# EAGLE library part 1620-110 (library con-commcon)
COMPACT PCI TYPE A - 110 PINS 2mm HARD METRIC SOCKETS

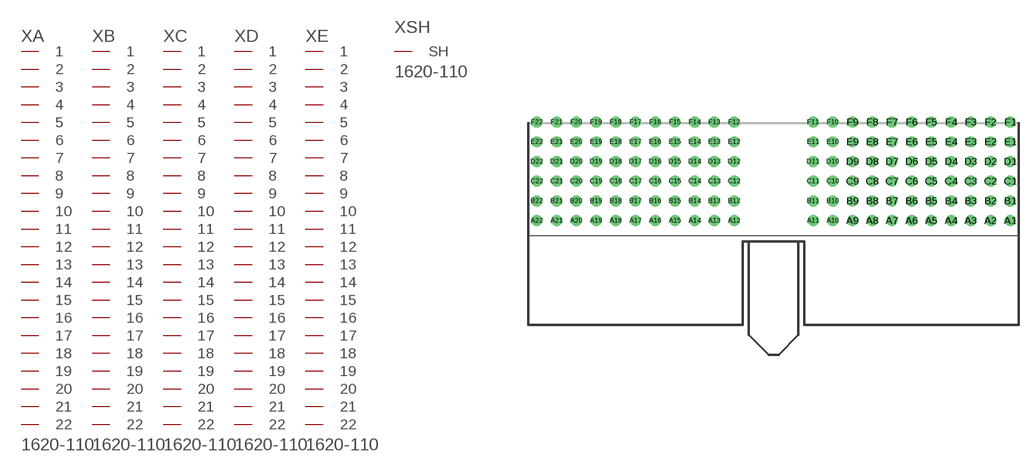
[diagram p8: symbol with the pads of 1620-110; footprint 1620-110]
Designator prefix X; gates A=PIN22 B=PIN22 C=PIN22 D=PIN22 E=PIN22 SH=SHIELD

## 1620-110  [1620-110]
A1  A:1  pas
A2  A:2  pas
A3  A:3  pas
A4  A:4  pas
A5  A:5  pas
A6  A:6  pas
A7  A:7  pas
A8  A:8  pas
A9  A:9  pas
A10  A:10  pas
A11  A:11  pas
A12  A:12  pas
A13  A:13  pas
A14  A:14  pas
A15  A:15  pas
A16  A:16  pas
A17  A:17  pas
A18  A:18  pas
A19  A:19  pas
A20  A:20  pas
A21  A:21  pas
A22  A:22  pas
B1  B:1  pas
B2  B:2  pas
B3  B:3  pas
B4  B:4  pas
B5  B:5  pas
B6  B:6  pas
B7  B:7  pas
B8  B:8  pas
B9  B:9  pas
B10  B:10  pas
B11  B:11  pas
B12  B:12  pas
B13  B:13  pas
B14  B:14  pas
B15  B:15  pas
B16  B:16  pas
B17  B:17  pas
B18  B:18  pas
B19  B:19  pas
B20  B:20  pas
B21  B:21  pas
B22  B:22  pas
C1  C:1  pas
C2  C:2  pas
C3  C:3  pas
C4  C:4  pas
C5  C:5  pas
C6  C:6  pas
C7  C:7  pas
C8  C:8  pas
C9  C:9  pas
C10  C:10  pas
C11  C:11  pas
C12  C:12  pas
C13  C:13  pas
C14  C:14  pas
C15  C:15  pas
C16  C:16  pas
C17  C:17  pas
C18  C:18  pas
C19  C:19  pas
C20  C:20  pas
C21  C:21  pas
C22  C:22  pas
D1  D:1  pas
D2  D:2  pas
D3  D:3  pas
D4  D:4  pas
D5  D:5  pas
D6  D:6  pas
D7  D:7  pas
D8  D:8  pas
D9  D:9  pas
D10  D:10  pas
D11  D:11  pas
D12  D:12  pas
D13  D:13  pas
D14  D:14  pas
D15  D:15  pas
D16  D:16  pas
D17  D:17  pas
D18  D:18  pas
D19  D:19  pas
D20  D:20  pas
D21  D:21  pas
D22  D:22  pas
E1  E:1  pas
E2  E:2  pas
E3  E:3  pas
E4  E:4  pas
E5  E:5  pas
E6  E:6  pas
E7  E:7  pas
E8  E:8  pas
E9  E:9  pas
E10  E:10  pas
E11  E:11  pas
E12  E:12  pas
E13  E:13  pas
E14  E:14  pas
E15  E:15  pas
E16  E:16  pas
E17  E:17  pas
E18  E:18  pas
E19  E:19  pas
E20  E:20  pas
E21  E:21  pas
E22  E:22  pas
F1  SH:SH  pas

## Footprint 1620-110 (pad centres in mm)
COMPACT PCI TYPE A - 110 PINS 2mm HARD METRIC SOCKETS
drill 0.6 round: A1 24,0; A2 22,0; A3 20,0; A4 18,0; A5 16,0; A6 14,0; A7 12,0; A8 10,0; A9 8,0; A10 6,0; A11 4,0; A12 -4,0; A13 -6,0; A14 -8,0; A15 -10,0; A16 -12,0; A17 -14,0; A18 -16,0; A19 -18,0; A20 -20,0; A21 -22,0; A22 -24,0; B1 24,2; B2 22,2; B3 20,2; B4 18,2; B5 16,2; B6 14,2; B7 12,2; B8 10,2; B9 8,2; B10 6,2; B11 4,2; B12 -4,2; B13 -6,2; B14 -8,2; B15 -10,2; B16 -12,2; B17 -14,2; B18 -16,2; B19 -18,2; B20 -20,2; B21 -22,2; B22 -24,2; C1 24,4; C2 22,4; C3 20,4; C4 18,4; C5 16,4; C6 14,4; C7 12,4; C8 10,4; C9 8,4; C10 6,4; C11 4,4; C12 -4,4; C13 -6,4; C14 -8,4; C15 -10,4; C16 -12,4; C17 -14,4; C18 -16,4; C19 -18,4; C20 -20,4; C21 -22,4; C22 -24,4; D1 24,6; D2 22,6; D3 20,6; D4 18,6; D5 16,6; D6 14,6; D7 12,6; D8 10,6; D9 8,6; D10 6,6; D11 4,6; D12 -4,6; D13 -6,6; D14 -8,6; D15 -10,6; D16 -12,6; D17 -14,6; D18 -16,6; D19 -18,6; D20 -20,6; D21 -22,6; D22 -24,6; E1 24,8; E2 22,8; E3 20,8; E4 18,8; E5 16,8; E6 14,8; E7 12,8; E8 10,8; E9 8,8; E10 6,8; E11 4,8; E12 -4,8; E13 -6,8; E14 -8,8; E15 -10,8; E16 -12,8; E17 -14,8; E18 -16,8; E19 -18,8; E20 -20,8; E21 -22,8; E22 -24,8; F1 24,10; F2 22,10; F3 20,10; F4 18,10; F5 16,10; F6 14,10; F7 12,10; F8 10,10; F9 8,10; F10 6,10; F11 4,10; F12 -4,10; F13 -6,10; F14 -8,10; F15 -10,10; F16 -12,10; F17 -14,10; F18 -16,10; F19 -18,10; F20 -20,10; F21 -22,10; F22 -24,10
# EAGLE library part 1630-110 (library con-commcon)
COMPACT PCI TYPE B - 110 PINS 2mm HARD METRIC SOCKETS

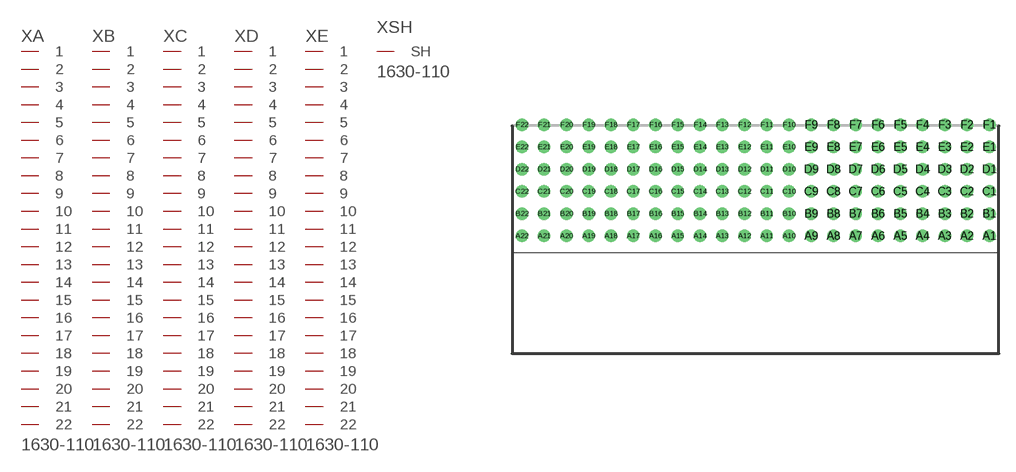
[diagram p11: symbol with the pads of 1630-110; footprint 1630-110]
Designator prefix X; gates A=PIN22 B=PIN22 C=PIN22 D=PIN22 E=PIN22 SH=SHIELD

## 1630-110  [1630-110]
A1  A:1  pas
A2  A:2  pas
A3  A:3  pas
A4  A:4  pas
A5  A:5  pas
A6  A:6  pas
A7  A:7  pas
A8  A:8  pas
A9  A:9  pas
A10  A:10  pas
A11  A:11  pas
A12  A:12  pas
A13  A:13  pas
A14  A:14  pas
A15  A:15  pas
A16  A:16  pas
A17  A:17  pas
A18  A:18  pas
A19  A:19  pas
A20  A:20  pas
A21  A:21  pas
A22  A:22  pas
B1  B:1  pas
B2  B:2  pas
B3  B:3  pas
B4  B:4  pas
B5  B:5  pas
B6  B:6  pas
B7  B:7  pas
B8  B:8  pas
B9  B:9  pas
B10  B:10  pas
B11  B:11  pas
B12  B:12  pas
B13  B:13  pas
B14  B:14  pas
B15  B:15  pas
B16  B:16  pas
B17  B:17  pas
B18  B:18  pas
B19  B:19  pas
B20  B:20  pas
B21  B:21  pas
B22  B:22  pas
C1  C:1  pas
C2  C:2  pas
C3  C:3  pas
C4  C:4  pas
C5  C:5  pas
C6  C:6  pas
C7  C:7  pas
C8  C:8  pas
C9  C:9  pas
C10  C:10  pas
C11  C:11  pas
C12  C:12  pas
C13  C:13  pas
C14  C:14  pas
C15  C:15  pas
C16  C:16  pas
C17  C:17  pas
C18  C:18  pas
C19  C:19  pas
C20  C:20  pas
C21  C:21  pas
C22  C:22  pas
D1  D:1  pas
D2  D:2  pas
D3  D:3  pas
D4  D:4  pas
D5  D:5  pas
D6  D:6  pas
D7  D:7  pas
D8  D:8  pas
D9  D:9  pas
D10  D:10  pas
D11  D:11  pas
D12  D:12  pas
D13  D:13  pas
D14  D:14  pas
D15  D:15  pas
D16  D:16  pas
D17  D:17  pas
D18  D:18  pas
D19  D:19  pas
D20  D:20  pas
D21  D:21  pas
D22  D:22  pas
E1  E:1  pas
E2  E:2  pas
E3  E:3  pas
E4  E:4  pas
E5  E:5  pas
E6  E:6  pas
E7  E:7  pas
E8  E:8  pas
E9  E:9  pas
E10  E:10  pas
E11  E:11  pas
E12  E:12  pas
E13  E:13  pas
E14  E:14  pas
E15  E:15  pas
E16  E:16  pas
E17  E:17  pas
E18  E:18  pas
E19  E:19  pas
E20  E:20  pas
E21  E:21  pas
E22  E:22  pas
F1  SH:SH  pas

## Footprint 1630-110 (pad centres in mm)
COMPACT PCI TYPE B - 110 PINS 2mm HARD METRIC SOCKETS
drill 0.6 round: A1 21,0; A2 19,0; A3 17,0; A4 15,0; A5 13,0; A6 11,0; A7 9,0; A8 7,0; A9 5,0; A10 3,0; A11 1,0; A12 -1,0; A13 -3,0; A14 -5,0; A15 -7,0; A16 -9,0; A17 -11,0; A18 -13,0; A19 -15,0; A20 -17,0; A21 -19,0; A22 -21,0; B1 21,2; B2 19,2; B3 17,2; B4 15,2; B5 13,2; B6 11,2; B7 9,2; B8 7,2; B9 5,2; B10 3,2; B11 1,2; B12 -1,2; B13 -3,2; B14 -5,2; B15 -7,2; B16 -9,2; B17 -11,2; B18 -13,2; B19 -15,2; B20 -17,2; B21 -19,2; B22 -21,2; C1 21,4; C2 19,4; C3 17,4; C4 15,4; C5 13,4; C6 11,4; C7 9,4; C8 7,4; C9 5,4; C10 3,4; C11 1,4; C12 -1,4; C13 -3,4; C14 -5,4; C15 -7,4; C16 -9,4; C17 -11,4; C18 -13,4; C19 -15,4; C20 -17,4; C21 -19,4; C22 -21,4; D1 21,6; D2 19,6; D3 17,6; D4 15,6; D5 13,6; D6 11,6; D7 9,6; D8 7,6; D9 5,6; D10 3,6; D11 1,6; D12 -1,6; D13 -3,6; D14 -5,6; D15 -7,6; D16 -9,6; D17 -11,6; D18 -13,6; D19 -15,6; D20 -17,6; D21 -19,6; D22 -21,6; E1 21,8; E2 19,8; E3 17,8; E4 15,8; E5 13,8; E6 11,8; E7 9,8; E8 7,8; E9 5,8; E10 3,8; E11 1,8; E12 -1,8; E13 -3,8; E14 -5,8; E15 -7,8; E16 -9,8; E17 -11,8; E18 -13,8; E19 -15,8; E20 -17,8; E21 -19,8; E22 -21,8; F1 21,10; F2 19,10; F3 17,10; F4 15,10; F5 13,10; F6 11,10; F7 9,10; F8 7,10; F9 5,10; F10 3,10; F11 1,10; F12 -1,10; F13 -3,10; F14 -5,10; F15 -7,10; F16 -9,10; F17 -11,10; F18 -13,10; F19 -15,10; F20 -17,10; F21 -19,10; F22 -21,10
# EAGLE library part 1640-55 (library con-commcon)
COMPACT PCI TYPE C - 55 PINS 2mm HARD METRIC SOCKETS

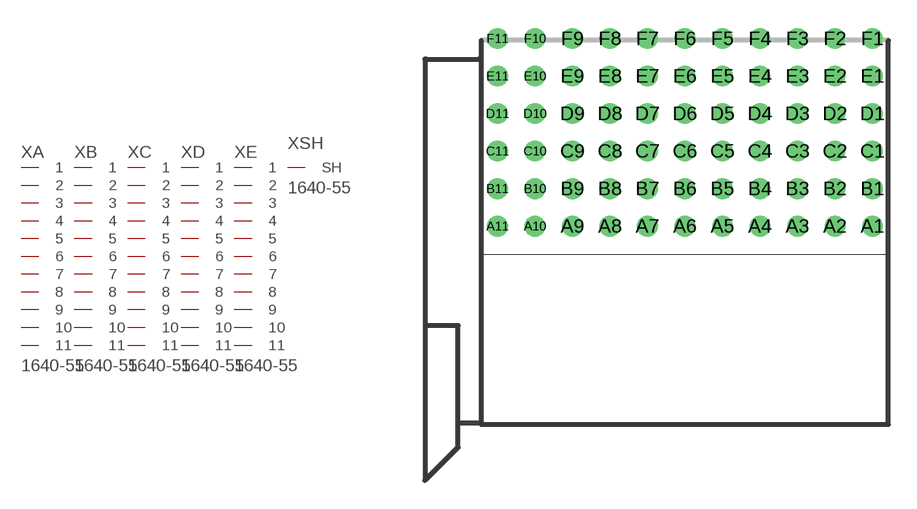
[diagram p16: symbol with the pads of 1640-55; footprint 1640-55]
Designator prefix X; gates A=PIN11 B=PIN11 C=PIN11 D=PIN11 E=PIN11 SH=SHIELD

## 1640-55  [1640-55]
A1  A:1  pas
A2  A:2  pas
A3  A:3  pas
A4  A:4  pas
A5  A:5  pas
A6  A:6  pas
A7  A:7  pas
A8  A:8  pas
A9  A:9  pas
A10  A:10  pas
A11  A:11  pas
B1  B:1  pas
B2  B:2  pas
B3  B:3  pas
B4  B:4  pas
B5  B:5  pas
B6  B:6  pas
B7  B:7  pas
B8  B:8  pas
B9  B:9  pas
B10  B:10  pas
B11  B:11  pas
C1  C:1  pas
C2  C:2  pas
C3  C:3  pas
C4  C:4  pas
C5  C:5  pas
C6  C:6  pas
C7  C:7  pas
C8  C:8  pas
C9  C:9  pas
C10  C:10  pas
C11  C:11  pas
D1  D:1  pas
D2  D:2  pas
D3  D:3  pas
D4  D:4  pas
D5  D:5  pas
D6  D:6  pas
D7  D:7  pas
D8  D:8  pas
D9  D:9  pas
D10  D:10  pas
D11  D:11  pas
E1  E:1  pas
E2  E:2  pas
E3  E:3  pas
E4  E:4  pas
E5  E:5  pas
E6  E:6  pas
E7  E:7  pas
E8  E:8  pas
E9  E:9  pas
E10  E:10  pas
E11  E:11  pas
F1  SH:SH  pas

## Footprint 1640-55 (pad centres in mm)
COMPACT PCI TYPE C - 55 PINS 2mm HARD METRIC SOCKETS
drill 0.6 round: A1 10,0; A2 8,0; A3 6,0; A4 4,0; A5 2,0; A6 0,0; A7 -2,0; A8 -4,0; A9 -6,0; A10 -8,0; A11 -10,0; B1 10,2; B2 8,2; B3 6,2; B4 4,2; B5 2,2; B6 0,2; B7 -2,2; B8 -4,2; B9 -6,2; B10 -8,2; B11 -10,2; C1 10,4; C2 8,4; C3 6,4; C4 4,4; C5 2,4; C6 0,4; C7 -2,4; C8 -4,4; C9 -6,4; C10 -8,4; C11 -10,4; D1 10,6; D2 8,6; D3 6,6; D4 4,6; D5 2,6; D6 0,6; D7 -2,6; D8 -4,6; D9 -6,6; D10 -8,6; D11 -10,6; E1 10,8; E2 8,8; E3 6,8; E4 4,8; E5 2,8; E6 0,8; E7 -2,8; E8 -4,8; E9 -6,8; E10 -8,8; E11 -10,8; F1 10,10; F2 8,10; F3 6,10; F4 4,10; F5 2,10; F6 0,10; F7 -2,10; F8 -4,10; F9 -6,10; F10 -8,10; F11 -10,10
